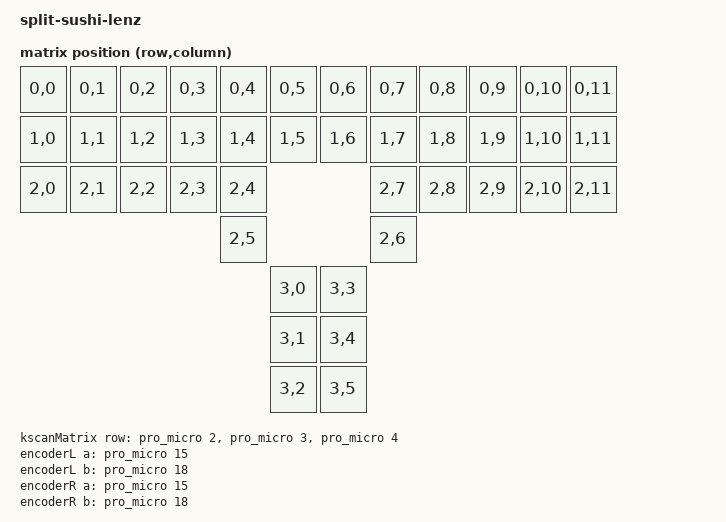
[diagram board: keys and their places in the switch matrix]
// This file was generated from a template. Edit it to match your keyboard.
// See https://docs.zephyrproject.org/4.1.0/hardware/porting/board_porting.html
// and https://zmk.dev/docs/development/hardware-integration/new-shield for more
// instructions.

/dts-v1/;
#include <dt-bindings/zmk/matrix_transform.h>

#include "split_sushi_lenz-layouts.dtsi"

/ {
    model = "split-sushi-lenz";
    compatible = "split_sushi_lenz";

    chosen {
        zmk,physical-layout = &default_layout;
		zmk,kscan = &kscan;
    };

    kscanMatrix: kscan_matrix {
        compatible = "zmk,kscan-gpio-matrix";
        diode-direction = "col2row";
        wakeup-source;

        // Replace these comments with the GPIO pins in the matrix.
        // See https://zmk.dev/docs/development/hardware-integration/new-shield#shield-overlays
        row-gpios
            = <&pro_micro 2 (GPIO_ACTIVE_HIGH | GPIO_PULL_DOWN)>
            , <&pro_micro 3 (GPIO_ACTIVE_HIGH | GPIO_PULL_DOWN)>
            , <&pro_micro 4 (GPIO_ACTIVE_HIGH | GPIO_PULL_DOWN)>
            ;
    };
	
	kscanDirect: kscan_direct {
		compatible = "zmk, kscan-gpio-direct";
		wakeup-source;
		toggle-mode;
		input-gpios
		= <&pro_micro 14 (GPIO_ACTIVE_LOW | GPIO_PULL_UP)>
        , <&pro_micro 16 (GPIO_ACTIVE_LOW | GPIO_PULL_UP)>
        , <&pro_micro 10 (GPIO_ACTIVE_LOW | GPIO_PULL_UP)>
	};
	 
	kscan: kscan_composite {
		compatible = "zmk,kscan-composite";
        columns = <12>;
        rows = <6>;
		
		matrix {
			kscan = <&kscanMatrix>
		};
		
		direct {
            kscan = <&kscanDirect>;
            row-offset = <3>; // ...and shift it to not overlap
        };
	};
	
	encoderL: encoder_left {
        compatible = "alps,ec11";
        a-gpios = <&pro_micro 15 (GPIO_ACTIVE_HIGH | GPIO_PULL_UP)>;
        b-gpios = <&pro_micro 18 (GPIO_ACTIVE_HIGH | GPIO_PULL_UP)>;
        steps = <30>;
        status = "disabled";
    };
	
	encoderR: encoder_right {
        compatible = "alps,ec11";
        a-gpios = <&pro_micro 15 (GPIO_ACTIVE_HIGH | GPIO_PULL_UP)>;
        b-gpios = <&pro_micro 18 (GPIO_ACTIVE_HIGH | GPIO_PULL_UP)>;
        steps = <30>;
        status = "disabled";
    };
	
    default_transform: default_transform {
        // See https://zmk.dev/docs/development/hardware-integration/new-shield#matrix-transform
        // for how to configure this
        compatible = "zmk,matrix-transform";
        columns = <12>;
        rows = <6>;

        map = <
            RC(0, 0) RC(0, 1) RC(0, 2) RC(0, 3) RC(0, 4) RC(0, 5)    RC(0, 6) RC(0, 7) RC(0, 8) RC(0, 9) RC(0, 10) RC(0, 11)
            RC(1, 0) RC(1, 1) RC(1, 2) RC(1, 3) RC(1, 4) RC(1, 5)    RC(1, 6) RC(1, 7) RC(1, 8) RC(1, 9) RC(1, 10) RC(1, 11)
            RC(2, 0) RC(2, 1) RC(2, 2) RC(2, 3) RC(2, 4)                      RC(2, 7) RC(2, 8) RC(2, 9) RC(2, 10) RC(2, 11)
													RC(2, 5)              RC(2, 6)
													  RC(3, 0)         	RC(3, 3)
													    RC(3, 1)      RC(3, 4)
														  RC(3, 2)  RC(3, 5)
        >;
    };
};
